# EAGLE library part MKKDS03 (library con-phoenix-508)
PHOENIX

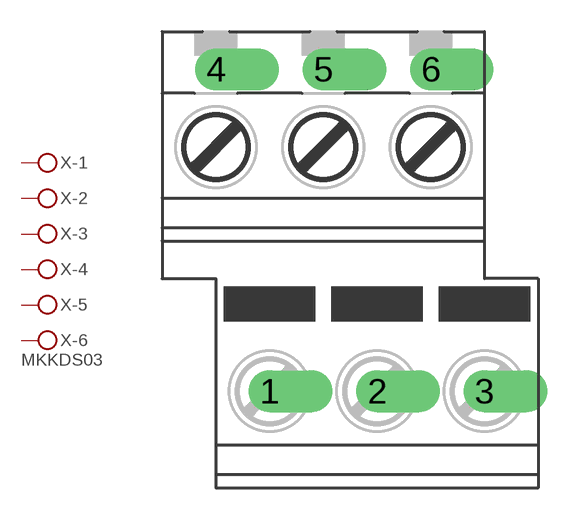
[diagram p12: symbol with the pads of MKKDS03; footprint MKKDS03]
Designator prefix X; gates -1=KL -2=KL -3=KL -4=KL -5=KL -6=KLV

## MKKDS03  [MKKDS03]
1  -1:KL  pas
2  -2:KL  pas
3  -3:KL  pas
4  -4:KL  pas
5  -5:KL  pas
6  -6:KL  pas

## Footprint MKKDS03 (pad centres in mm)
PHOENIX
drill 1.321 offset: 1 -3.81,-6.35; 2 1.27,-6.35; 3 6.35,-6.35; 4 -6.35,8.89; 5 -1.27,8.89; 6 3.81,8.89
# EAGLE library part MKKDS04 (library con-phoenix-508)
PHOENIX

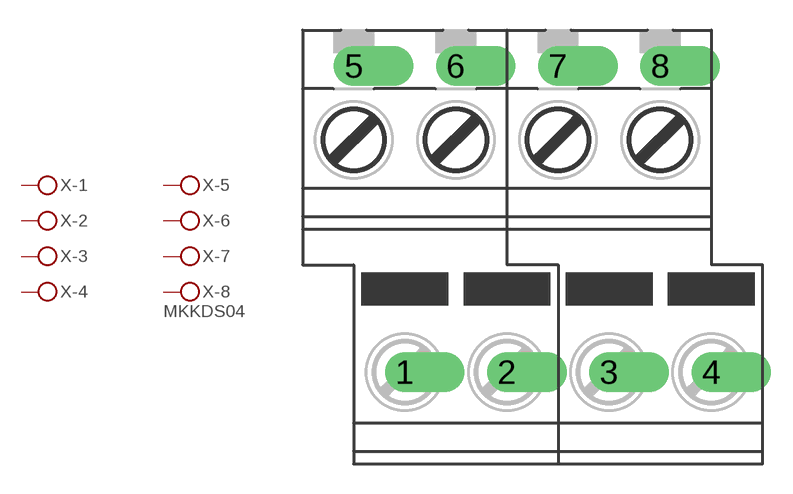
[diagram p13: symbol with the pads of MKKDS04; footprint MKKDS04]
Designator prefix X; gates -1=KL -2=KL -3=KL -4=KL -5=KL -6=KL -7=KL -8=KLV

## MKKDS04  [MKKDS04]
1  -1:KL  pas
2  -2:KL  pas
3  -3:KL  pas
4  -4:KL  pas
5  -5:KL  pas
6  -6:KL  pas
7  -7:KL  pas
8  -8:KL  pas

## Footprint MKKDS04 (pad centres in mm)
PHOENIX
drill 1.321 offset: 1 -6.35,-6.35; 2 -1.27,-6.35; 3 3.81,-6.35; 4 8.89,-6.35; 5 -8.89,8.89; 6 -3.81,8.89; 7 1.27,8.89; 8 6.35,8.89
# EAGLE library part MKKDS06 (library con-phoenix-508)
PHOENIX

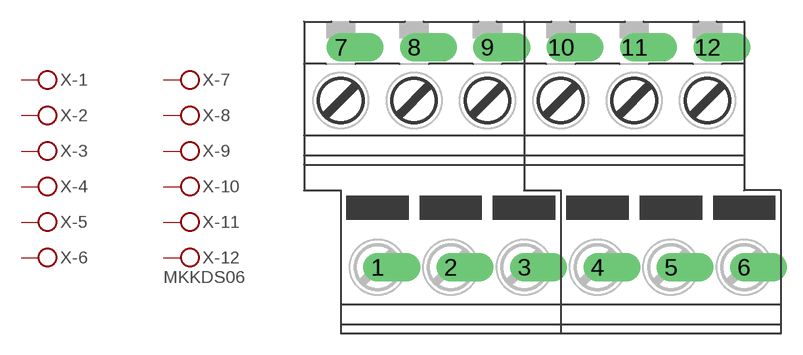
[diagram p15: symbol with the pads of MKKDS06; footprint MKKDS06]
Designator prefix X; gates -1=KL -2=KL -3=KL -4=KL -5=KL -6=KL -7=KL -8=KL -9=KL -10=KL -11=KL -12=KLV

## MKKDS06  [MKKDS06]
1  -1:KL  pas
2  -2:KL  pas
3  -3:KL  pas
4  -4:KL  pas
5  -5:KL  pas
6  -6:KL  pas
7  -7:KL  pas
8  -8:KL  pas
9  -9:KL  pas
10  -10:KL  pas
11  -11:KL  pas
12  -12:KL  pas

## Footprint MKKDS06 (pad centres in mm)
PHOENIX
drill 1.321 offset: 1 -11.43,-6.35; 2 -6.35,-6.35; 3 -1.27,-6.35; 4 3.81,-6.35; 5 8.89,-6.35; 6 13.97,-6.35; 7 -13.97,8.89; 8 -8.89,8.89; 9 -3.81,8.89; 10 1.27,8.89; 11 6.35,8.89; 12 11.43,8.89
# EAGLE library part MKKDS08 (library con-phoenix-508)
PHOENIX

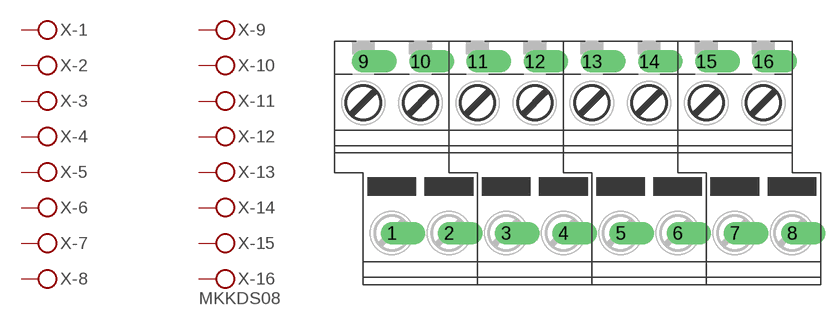
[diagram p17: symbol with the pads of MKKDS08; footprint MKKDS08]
Designator prefix X; gates -1=KL -2=KL -3=KL -4=KL -5=KL -6=KL -7=KL -8=KL -9=KL -10=KL -11=KL -12=KL -13=KL -14=KL -15=KL -16=KLV

## MKKDS08  [MKKDS08]
1  -1:KL  pas
2  -2:KL  pas
3  -3:KL  pas
4  -4:KL  pas
5  -5:KL  pas
6  -6:KL  pas
7  -7:KL  pas
8  -8:KL  pas
9  -9:KL  pas
10  -10:KL  pas
11  -11:KL  pas
12  -12:KL  pas
13  -13:KL  pas
14  -14:KL  pas
15  -15:KL  pas
16  -16:KL  pas

## Footprint MKKDS08 (pad centres in mm)
PHOENIX
drill 1.321 offset: 1 -16.51,-6.35; 2 -11.43,-6.35; 3 -6.35,-6.35; 4 -1.27,-6.35; 5 3.81,-6.35; 6 8.89,-6.35; 7 13.97,-6.35; 8 19.05,-6.35; 9 -19.05,8.89; 10 -13.97,8.89; 11 -8.89,8.89; 12 -3.81,8.89; 13 1.27,8.89; 14 6.35,8.89; 15 11.43,8.89; 16 16.51,8.89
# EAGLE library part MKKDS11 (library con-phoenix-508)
PHOENIX

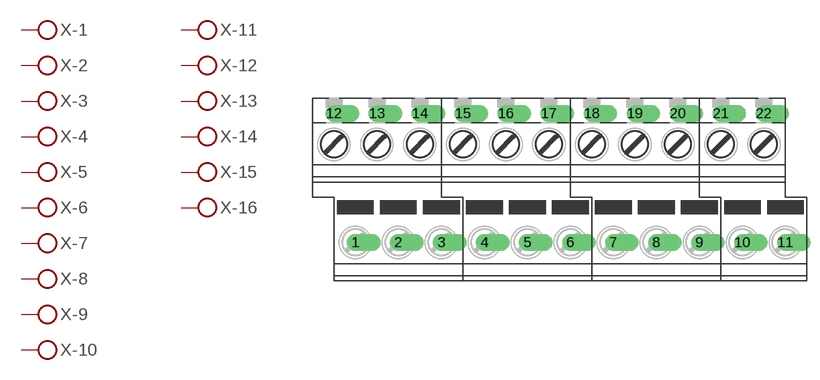
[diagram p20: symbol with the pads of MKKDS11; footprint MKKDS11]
Designator prefix X; gates -1=KL -2=KL -3=KL -4=KL -5=KL -6=KL -7=KL -8=KL -9=KL -10=KL -11=KL -12=KL -13=KL -14=KL -15=KL -16=KL -17=KL -18=KL -19=KL -20=KL -21=KL -22=KLV

## MKKDS11  [MKKDS11]
1  -1:KL  pas
2  -2:KL  pas
3  -3:KL  pas
4  -4:KL  pas
5  -5:KL  pas
6  -6:KL  pas
7  -7:KL  pas
8  -8:KL  pas
9  -9:KL  pas
10  -10:KL  pas
11  -11:KL  pas
12  -12:KL  pas
13  -13:KL  pas
14  -14:KL  pas
15  -15:KL  pas
16  -16:KL  pas
17  -17:KL  pas
18  -18:KL  pas
19  -19:KL  pas
20  -20:KL  pas
21  -21:KL  pas
22  -22:KL  pas

## Footprint MKKDS11 (pad centres in mm)
PHOENIX
drill 1.321 offset: 1 -24.13,-6.35; 2 -19.05,-6.35; 3 -13.97,-6.35; 4 -8.89,-6.35; 5 -3.81,-6.35; 6 1.27,-6.35; 7 6.35,-6.35; 8 11.43,-6.35; 9 16.51,-6.35; 10 21.59,-6.35; 11 26.67,-6.35; 12 -26.67,8.89; 13 -21.59,8.89; 14 -16.51,8.89; 15 -11.43,8.89; 16 -6.35,8.89; 17 -1.27,8.89; 18 3.81,8.89; 19 8.89,8.89; 20 13.97,8.89; 21 19.05,8.89; 22 24.13,8.89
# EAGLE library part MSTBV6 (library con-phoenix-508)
PHOENIX

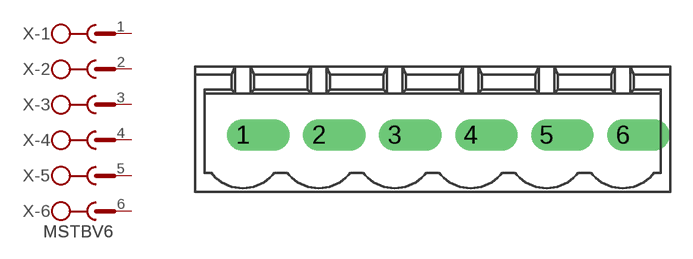
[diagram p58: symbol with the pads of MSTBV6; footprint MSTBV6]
Designator prefix X; gates -1=SK -2=SK -3=SK -4=SK -5=SK -6=SKV

## MSTBV6  [MSTBV6]
1  -1:1  pas
2  -2:1  pas
3  -3:1  pas
4  -4:1  pas
5  -5:1  pas
6  -6:1  pas

## Footprint MSTBV6 (pad centres in mm)
PHOENIX
drill 1.397 offset: 1 -12.7,0; 2 -7.62,0; 3 -2.54,0; 4 2.54,0; 5 7.62,0; 6 12.7,0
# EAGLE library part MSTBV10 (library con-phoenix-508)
PHOENIX

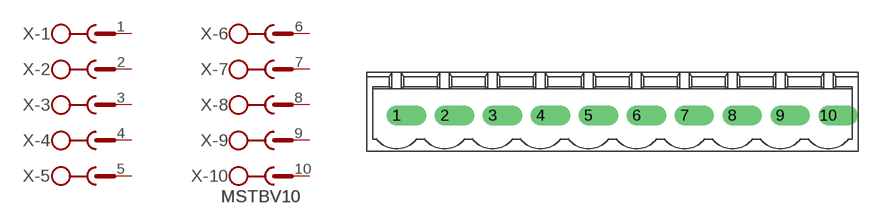
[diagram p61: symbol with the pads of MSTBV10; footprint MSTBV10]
Designator prefix X; gates -1=SK -2=SK -3=SK -4=SK -5=SK -6=SK -7=SK -8=SK -9=SK -10=SKV

## MSTBV10  [MSTBV10]
1  -1:1  pas
2  -2:1  pas
3  -3:1  pas
4  -4:1  pas
5  -5:1  pas
6  -6:1  pas
7  -7:1  pas
8  -8:1  pas
9  -9:1  pas
10  -10:1  pas

## Footprint MSTBV10 (pad centres in mm)
PHOENIX
drill 1.397 offset: 1 -22.86,0; 2 -17.78,0; 3 -12.7,0; 4 -7.62,0; 5 -2.54,0; 6 2.54,0; 7 7.62,0; 8 12.7,0; 9 17.78,0; 10 22.86,0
